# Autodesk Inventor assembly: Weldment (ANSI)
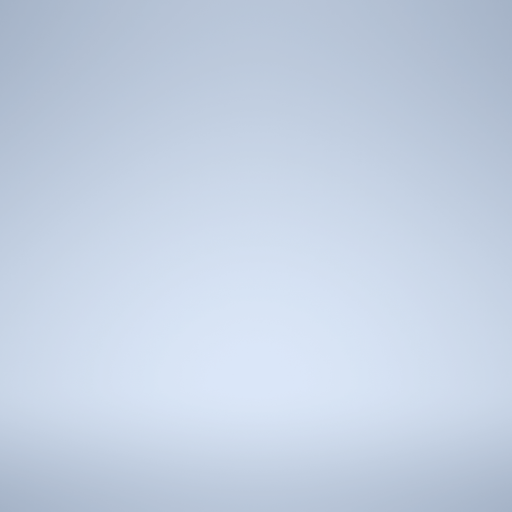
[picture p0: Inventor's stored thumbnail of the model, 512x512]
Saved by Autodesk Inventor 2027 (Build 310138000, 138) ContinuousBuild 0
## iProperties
Length Units: 11272
Angle Units: 11286
Time Units: 11279
Mass Units: 11290
Length Display Precision: 3
Angle Display Precision: 2
Part Number: Weldment (ANSI)
Document SubType Name: Weldment
Created: 2002-06
Designer: smithga
Created: 2002-08
Weld Material: Welded Aluminum-6061
Control State: 0
Master: False
Shininess: 64.0
Angle Units: 11279
Time Units: 11290
Mass Units: 11286
Compacted: True
Density: 0.0
Volumn: 0.0
Area: 0.0
PropertySet Name: Model Information
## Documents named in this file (1)
- D:\AUTOBUILD\inventor\Application\App\Templates\en-US\English\Weldment (ANSI).iam
